VERSION 5.7 ;
  NOWIREEXTENSIONATPIN ON ;
  DIVIDERCHAR "/" ;
  BUSBITCHARS "[]" ;
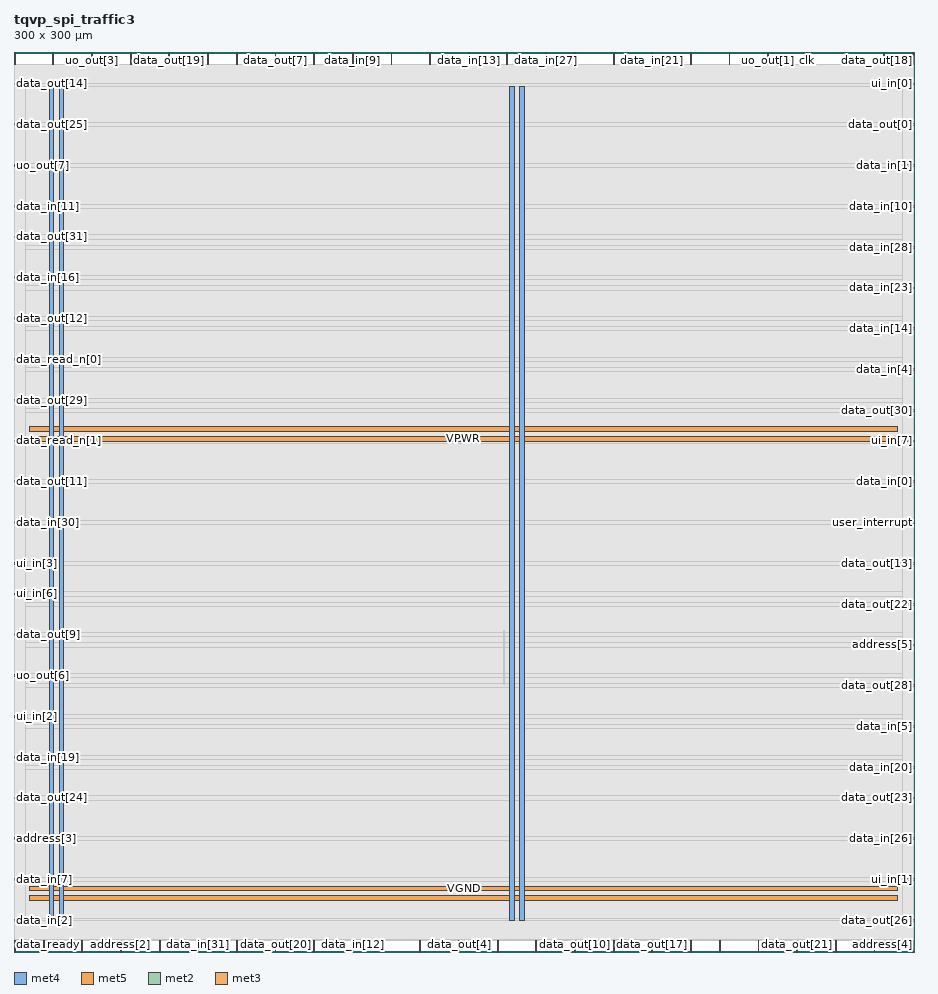
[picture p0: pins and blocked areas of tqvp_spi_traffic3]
MACRO tqvp_spi_traffic3
  CLASS BLOCK ;
  FOREIGN tqvp_spi_traffic3 ;
  ORIGIN 0.000 0.000 ;
  SIZE 300.000 BY 300.000 ;
  PIN VGND
    DIRECTION INOUT ;
    USE GROUND ;
    PORT
      LAYER met4 ;
        RECT 15.020 10.640 16.620 288.560 ;
    END
    PORT
      LAYER met4 ;
        RECT 168.620 10.640 170.220 288.560 ;
    END
    PORT
      LAYER met5 ;
        RECT 5.280 20.380 294.640 21.980 ;
    END
    PORT
      LAYER met5 ;
        RECT 5.280 173.560 294.640 175.160 ;
    END
  END VGND
  PIN VPWR
    DIRECTION INOUT ;
    USE POWER ;
    PORT
      LAYER met4 ;
        RECT 11.720 10.640 13.320 288.560 ;
    END
    PORT
      LAYER met4 ;
        RECT 165.320 10.640 166.920 288.560 ;
    END
    PORT
      LAYER met5 ;
        RECT 5.280 17.080 294.640 18.680 ;
    END
    PORT
      LAYER met5 ;
        RECT 5.280 170.260 294.640 171.860 ;
    END
  END VPWR
  PIN address[0]
    DIRECTION INPUT ;
    USE SIGNAL ;
    PORT
      LAYER met2 ;
        RECT 99.910 296.000 100.190 300.000 ;
    END
  END address[0]
  PIN address[1]
    DIRECTION INPUT ;
    USE SIGNAL ;
    PORT
      LAYER met2 ;
        RECT 199.730 296.000 200.010 300.000 ;
    END
  END address[1]
  PIN address[2]
    DIRECTION INPUT ;
    USE SIGNAL ;
    ANTENNAGATEAREA 0.593700 ;
    ANTENNADIFFAREA 0.434700 ;
    PORT
      LAYER met2 ;
        RECT 35.510 0.000 35.790 4.000 ;
    END
  END address[2]
  PIN address[3]
    DIRECTION INPUT ;
    USE SIGNAL ;
    ANTENNAGATEAREA 0.593700 ;
    ANTENNADIFFAREA 0.434700 ;
    PORT
      LAYER met3 ;
        RECT 0.000 37.440 4.000 38.040 ;
    END
  END address[3]
  PIN address[4]
    DIRECTION INPUT ;
    USE SIGNAL ;
    ANTENNAGATEAREA 0.647700 ;
    ANTENNADIFFAREA 0.434700 ;
    PORT
      LAYER met2 ;
        RECT 299.550 0.000 299.830 4.000 ;
    END
  END address[4]
  PIN address[5]
    DIRECTION INPUT ;
    USE SIGNAL ;
    ANTENNAGATEAREA 0.593700 ;
    ANTENNADIFFAREA 0.434700 ;
    PORT
      LAYER met3 ;
        RECT 296.000 102.040 300.000 102.640 ;
    END
  END address[5]
  PIN clk
    DIRECTION INPUT ;
    USE SIGNAL ;
    ANTENNAGATEAREA 1.286700 ;
    ANTENNADIFFAREA 0.434700 ;
    PORT
      LAYER met2 ;
        RECT 264.130 296.000 264.410 300.000 ;
    END
  END clk
  PIN data_in[0]
    DIRECTION INPUT ;
    USE SIGNAL ;
    ANTENNAGATEAREA 0.593700 ;
    ANTENNADIFFAREA 0.434700 ;
    PORT
      LAYER met3 ;
        RECT 296.000 156.440 300.000 157.040 ;
    END
  END data_in[0]
  PIN data_in[10]
    DIRECTION INPUT ;
    USE SIGNAL ;
    PORT
      LAYER met3 ;
        RECT 296.000 248.240 300.000 248.840 ;
    END
  END data_in[10]
  PIN data_in[11]
    DIRECTION INPUT ;
    USE SIGNAL ;
    PORT
      LAYER met3 ;
        RECT 0.000 248.240 4.000 248.840 ;
    END
  END data_in[11]
  PIN data_in[12]
    DIRECTION INPUT ;
    USE SIGNAL ;
    PORT
      LAYER met2 ;
        RECT 112.790 0.000 113.070 4.000 ;
    END
  END data_in[12]
  PIN data_in[13]
    DIRECTION INPUT ;
    USE SIGNAL ;
    PORT
      LAYER met2 ;
        RECT 151.430 296.000 151.710 300.000 ;
    END
  END data_in[13]
  PIN data_in[14]
    DIRECTION INPUT ;
    USE SIGNAL ;
    PORT
      LAYER met3 ;
        RECT 296.000 207.440 300.000 208.040 ;
    END
  END data_in[14]
  PIN data_in[15]
    DIRECTION INPUT ;
    USE SIGNAL ;
    PORT
      LAYER met2 ;
        RECT 286.670 0.000 286.950 4.000 ;
    END
  END data_in[15]
  PIN data_in[16]
    DIRECTION INPUT ;
    USE SIGNAL ;
    PORT
      LAYER met3 ;
        RECT 0.000 224.440 4.000 225.040 ;
    END
  END data_in[16]
  PIN data_in[17]
    DIRECTION INPUT ;
    USE SIGNAL ;
    PORT
      LAYER met2 ;
        RECT 12.970 296.000 13.250 300.000 ;
    END
  END data_in[17]
  PIN data_in[18]
    DIRECTION INPUT ;
    USE SIGNAL ;
    PORT
      LAYER met2 ;
        RECT 125.670 296.000 125.950 300.000 ;
    END
  END data_in[18]
  PIN data_in[19]
    DIRECTION INPUT ;
    USE SIGNAL ;
    PORT
      LAYER met3 ;
        RECT 0.000 64.640 4.000 65.240 ;
    END
  END data_in[19]
  PIN data_in[1]
    DIRECTION INPUT ;
    USE SIGNAL ;
    ANTENNAGATEAREA 0.647700 ;
    ANTENNADIFFAREA 0.434700 ;
    PORT
      LAYER met3 ;
        RECT 296.000 261.840 300.000 262.440 ;
    END
  END data_in[1]
  PIN data_in[20]
    DIRECTION INPUT ;
    USE SIGNAL ;
    PORT
      LAYER met3 ;
        RECT 296.000 61.240 300.000 61.840 ;
    END
  END data_in[20]
  PIN data_in[21]
    DIRECTION INPUT ;
    USE SIGNAL ;
    PORT
      LAYER met2 ;
        RECT 212.610 296.000 212.890 300.000 ;
    END
  END data_in[21]
  PIN data_in[22]
    DIRECTION INPUT ;
    USE SIGNAL ;
    PORT
      LAYER met2 ;
        RECT 74.150 0.000 74.430 4.000 ;
    END
  END data_in[22]
  PIN data_in[23]
    DIRECTION INPUT ;
    USE SIGNAL ;
    PORT
      LAYER met3 ;
        RECT 296.000 221.040 300.000 221.640 ;
    END
  END data_in[23]
  PIN data_in[24]
    DIRECTION INPUT ;
    USE SIGNAL ;
    PORT
      LAYER met2 ;
        RECT 235.150 0.000 235.430 4.000 ;
    END
  END data_in[24]
  PIN data_in[25]
    DIRECTION INPUT ;
    USE SIGNAL ;
    PORT
      LAYER met2 ;
        RECT 277.010 296.000 277.290 300.000 ;
    END
  END data_in[25]
  PIN data_in[26]
    DIRECTION INPUT ;
    USE SIGNAL ;
    PORT
      LAYER met3 ;
        RECT 296.000 37.440 300.000 38.040 ;
    END
  END data_in[26]
  PIN data_in[27]
    DIRECTION INPUT ;
    USE SIGNAL ;
    PORT
      LAYER met2 ;
        RECT 177.190 296.000 177.470 300.000 ;
    END
  END data_in[27]
  PIN data_in[28]
    DIRECTION INPUT ;
    USE SIGNAL ;
    PORT
      LAYER met3 ;
        RECT 296.000 234.640 300.000 235.240 ;
    END
  END data_in[28]
  PIN data_in[29]
    DIRECTION INPUT ;
    USE SIGNAL ;
    PORT
      LAYER met2 ;
        RECT 0.090 296.000 0.370 300.000 ;
    END
  END data_in[29]
  PIN data_in[2]
    DIRECTION INPUT ;
    USE SIGNAL ;
    ANTENNAGATEAREA 0.593700 ;
    ANTENNADIFFAREA 0.434700 ;
    PORT
      LAYER met3 ;
        RECT 0.000 10.240 4.000 10.840 ;
    END
  END data_in[2]
  PIN data_in[30]
    DIRECTION INPUT ;
    USE SIGNAL ;
    PORT
      LAYER met3 ;
        RECT 0.000 142.840 4.000 143.440 ;
    END
  END data_in[30]
  PIN data_in[31]
    DIRECTION INPUT ;
    USE SIGNAL ;
    PORT
      LAYER met2 ;
        RECT 61.270 0.000 61.550 4.000 ;
    END
  END data_in[31]
  PIN data_in[3]
    DIRECTION INPUT ;
    USE SIGNAL ;
    ANTENNAGATEAREA 0.593700 ;
    ANTENNADIFFAREA 0.434700 ;
    PORT
      LAYER met2 ;
        RECT 138.550 296.000 138.830 300.000 ;
    END
  END data_in[3]
  PIN data_in[4]
    DIRECTION INPUT ;
    USE SIGNAL ;
    PORT
      LAYER met3 ;
        RECT 296.000 193.840 300.000 194.440 ;
    END
  END data_in[4]
  PIN data_in[5]
    DIRECTION INPUT ;
    USE SIGNAL ;
    PORT
      LAYER met3 ;
        RECT 296.000 74.840 300.000 75.440 ;
    END
  END data_in[5]
  PIN data_in[6]
    DIRECTION INPUT ;
    USE SIGNAL ;
    PORT
      LAYER met2 ;
        RECT 186.850 296.000 187.130 300.000 ;
    END
  END data_in[6]
  PIN data_in[7]
    DIRECTION INPUT ;
    USE SIGNAL ;
    PORT
      LAYER met3 ;
        RECT 0.000 23.840 4.000 24.440 ;
    END
  END data_in[7]
  PIN data_in[8]
    DIRECTION INPUT ;
    USE SIGNAL ;
    PORT
      LAYER met2 ;
        RECT 273.790 0.000 274.070 4.000 ;
    END
  END data_in[8]
  PIN data_in[9]
    DIRECTION INPUT ;
    USE SIGNAL ;
    PORT
      LAYER met2 ;
        RECT 112.790 296.000 113.070 300.000 ;
    END
  END data_in[9]
  PIN data_out[0]
    DIRECTION OUTPUT TRISTATE ;
    USE SIGNAL ;
    ANTENNADIFFAREA 0.795200 ;
    PORT
      LAYER met3 ;
        RECT 296.000 275.440 300.000 276.040 ;
    END
  END data_out[0]
  PIN data_out[10]
    DIRECTION OUTPUT TRISTATE ;
    USE SIGNAL ;
    ANTENNADIFFAREA 0.795200 ;
    PORT
      LAYER met2 ;
        RECT 186.850 0.000 187.130 4.000 ;
    END
  END data_out[10]
  PIN data_out[11]
    DIRECTION OUTPUT TRISTATE ;
    USE SIGNAL ;
    ANTENNADIFFAREA 0.795200 ;
    PORT
      LAYER met3 ;
        RECT 0.000 156.440 4.000 157.040 ;
    END
  END data_out[11]
  PIN data_out[12]
    DIRECTION OUTPUT TRISTATE ;
    USE SIGNAL ;
    ANTENNADIFFAREA 0.795200 ;
    PORT
      LAYER met3 ;
        RECT 0.000 210.840 4.000 211.440 ;
    END
  END data_out[12]
  PIN data_out[13]
    DIRECTION OUTPUT TRISTATE ;
    USE SIGNAL ;
    ANTENNADIFFAREA 0.795200 ;
    PORT
      LAYER met3 ;
        RECT 296.000 129.240 300.000 129.840 ;
    END
  END data_out[13]
  PIN data_out[14]
    DIRECTION OUTPUT TRISTATE ;
    USE SIGNAL ;
    ANTENNADIFFAREA 0.795200 ;
    PORT
      LAYER met3 ;
        RECT 0.000 289.040 4.000 289.640 ;
    END
  END data_out[14]
  PIN data_out[15]
    DIRECTION OUTPUT TRISTATE ;
    USE SIGNAL ;
    ANTENNADIFFAREA 0.795200 ;
    PORT
      LAYER met2 ;
        RECT 248.030 0.000 248.310 4.000 ;
    END
  END data_out[15]
  PIN data_out[16]
    DIRECTION OUTPUT TRISTATE ;
    USE SIGNAL ;
    ANTENNADIFFAREA 0.795200 ;
    PORT
      LAYER met2 ;
        RECT 122.450 0.000 122.730 4.000 ;
    END
  END data_out[16]
  PIN data_out[17]
    DIRECTION OUTPUT TRISTATE ;
    USE SIGNAL ;
    ANTENNADIFFAREA 0.795200 ;
    PORT
      LAYER met2 ;
        RECT 212.610 0.000 212.890 4.000 ;
    END
  END data_out[17]
  PIN data_out[18]
    DIRECTION OUTPUT TRISTATE ;
    USE SIGNAL ;
    ANTENNADIFFAREA 0.795200 ;
    PORT
      LAYER met2 ;
        RECT 299.550 296.000 299.830 300.000 ;
    END
  END data_out[18]
  PIN data_out[19]
    DIRECTION OUTPUT TRISTATE ;
    USE SIGNAL ;
    ANTENNADIFFAREA 0.795200 ;
    PORT
      LAYER met2 ;
        RECT 51.610 296.000 51.890 300.000 ;
    END
  END data_out[19]
  PIN data_out[1]
    DIRECTION OUTPUT TRISTATE ;
    USE SIGNAL ;
    ANTENNADIFFAREA 0.795200 ;
    PORT
      LAYER met2 ;
        RECT 22.630 0.000 22.910 4.000 ;
    END
  END data_out[1]
  PIN data_out[20]
    DIRECTION OUTPUT TRISTATE ;
    USE SIGNAL ;
    ANTENNADIFFAREA 0.795200 ;
    PORT
      LAYER met2 ;
        RECT 87.030 0.000 87.310 4.000 ;
    END
  END data_out[20]
  PIN data_out[21]
    DIRECTION OUTPUT TRISTATE ;
    USE SIGNAL ;
    ANTENNADIFFAREA 0.795200 ;
    PORT
      LAYER met2 ;
        RECT 260.910 0.000 261.190 4.000 ;
    END
  END data_out[21]
  PIN data_out[22]
    DIRECTION OUTPUT TRISTATE ;
    USE SIGNAL ;
    ANTENNADIFFAREA 0.795200 ;
    PORT
      LAYER met3 ;
        RECT 296.000 115.640 300.000 116.240 ;
    END
  END data_out[22]
  PIN data_out[23]
    DIRECTION OUTPUT TRISTATE ;
    USE SIGNAL ;
    ANTENNADIFFAREA 0.445500 ;
    PORT
      LAYER met3 ;
        RECT 296.000 51.040 300.000 51.640 ;
    END
  END data_out[23]
  PIN data_out[24]
    DIRECTION OUTPUT TRISTATE ;
    USE SIGNAL ;
    ANTENNADIFFAREA 0.795200 ;
    PORT
      LAYER met3 ;
        RECT 0.000 51.040 4.000 51.640 ;
    END
  END data_out[24]
  PIN data_out[25]
    DIRECTION OUTPUT TRISTATE ;
    USE SIGNAL ;
    PORT
      LAYER met3 ;
        RECT 0.000 275.440 4.000 276.040 ;
    END
  END data_out[25]
  PIN data_out[26]
    DIRECTION OUTPUT TRISTATE ;
    USE SIGNAL ;
    PORT
      LAYER met3 ;
        RECT 296.000 10.240 300.000 10.840 ;
    END
  END data_out[26]
  PIN data_out[27]
    DIRECTION OUTPUT TRISTATE ;
    USE SIGNAL ;
    PORT
      LAYER met2 ;
        RECT 64.490 296.000 64.770 300.000 ;
    END
  END data_out[27]
  PIN data_out[28]
    DIRECTION OUTPUT TRISTATE ;
    USE SIGNAL ;
    PORT
      LAYER met3 ;
        RECT 296.000 88.440 300.000 89.040 ;
    END
  END data_out[28]
  PIN data_out[29]
    DIRECTION OUTPUT TRISTATE ;
    USE SIGNAL ;
    PORT
      LAYER met3 ;
        RECT 0.000 183.640 4.000 184.240 ;
    END
  END data_out[29]
  PIN data_out[2]
    DIRECTION OUTPUT TRISTATE ;
    USE SIGNAL ;
    ANTENNADIFFAREA 0.795200 ;
    PORT
      LAYER met2 ;
        RECT 225.490 0.000 225.770 4.000 ;
    END
  END data_out[2]
  PIN data_out[30]
    DIRECTION OUTPUT TRISTATE ;
    USE SIGNAL ;
    PORT
      LAYER met3 ;
        RECT 296.000 180.240 300.000 180.840 ;
    END
  END data_out[30]
  PIN data_out[31]
    DIRECTION OUTPUT TRISTATE ;
    USE SIGNAL ;
    PORT
      LAYER met3 ;
        RECT 0.000 238.040 4.000 238.640 ;
    END
  END data_out[31]
  PIN data_out[3]
    DIRECTION OUTPUT TRISTATE ;
    USE SIGNAL ;
    ANTENNADIFFAREA 0.795200 ;
    PORT
      LAYER met2 ;
        RECT 38.730 296.000 39.010 300.000 ;
    END
  END data_out[3]
  PIN data_out[4]
    DIRECTION OUTPUT TRISTATE ;
    USE SIGNAL ;
    ANTENNADIFFAREA 0.795200 ;
    PORT
      LAYER met2 ;
        RECT 148.210 0.000 148.490 4.000 ;
    END
  END data_out[4]
  PIN data_out[5]
    DIRECTION OUTPUT TRISTATE ;
    USE SIGNAL ;
    ANTENNADIFFAREA 0.795200 ;
    PORT
      LAYER met2 ;
        RECT 0.090 0.000 0.370 4.000 ;
    END
  END data_out[5]
  PIN data_out[6]
    DIRECTION OUTPUT TRISTATE ;
    USE SIGNAL ;
    ANTENNADIFFAREA 0.795200 ;
    PORT
      LAYER met2 ;
        RECT 173.970 0.000 174.250 4.000 ;
    END
  END data_out[6]
  PIN data_out[7]
    DIRECTION OUTPUT TRISTATE ;
    USE SIGNAL ;
    ANTENNADIFFAREA 0.795200 ;
    PORT
      LAYER met2 ;
        RECT 87.030 296.000 87.310 300.000 ;
    END
  END data_out[7]
  PIN data_out[8]
    DIRECTION OUTPUT TRISTATE ;
    USE SIGNAL ;
    ANTENNADIFFAREA 0.795200 ;
    PORT
      LAYER met2 ;
        RECT 164.310 296.000 164.590 300.000 ;
    END
  END data_out[8]
  PIN data_out[9]
    DIRECTION OUTPUT TRISTATE ;
    USE SIGNAL ;
    ANTENNADIFFAREA 0.795200 ;
    PORT
      LAYER met3 ;
        RECT 0.000 105.440 4.000 106.040 ;
    END
  END data_out[9]
  PIN data_read_n[0]
    DIRECTION INPUT ;
    USE SIGNAL ;
    ANTENNAGATEAREA 0.631200 ;
    ANTENNADIFFAREA 0.434700 ;
    PORT
      LAYER met3 ;
        RECT 0.000 197.240 4.000 197.840 ;
    END
  END data_read_n[0]
  PIN data_read_n[1]
    DIRECTION INPUT ;
    USE SIGNAL ;
    ANTENNAGATEAREA 0.631200 ;
    ANTENNADIFFAREA 0.434700 ;
    PORT
      LAYER met3 ;
        RECT 0.000 170.040 4.000 170.640 ;
    END
  END data_read_n[1]
  PIN data_ready
    DIRECTION INPUT ;
    USE SIGNAL ;
    PORT
      LAYER met2 ;
        RECT 9.750 0.000 10.030 4.000 ;
    END
  END data_ready
  PIN data_write_n[0]
    DIRECTION INPUT ;
    USE SIGNAL ;
    ANTENNAGATEAREA 0.560700 ;
    ANTENNADIFFAREA 0.434700 ;
    PORT
      LAYER met2 ;
        RECT 289.890 296.000 290.170 300.000 ;
    END
  END data_write_n[0]
  PIN data_write_n[1]
    DIRECTION INPUT ;
    USE SIGNAL ;
    ANTENNAGATEAREA 0.631200 ;
    ANTENNADIFFAREA 0.434700 ;
    PORT
      LAYER met2 ;
        RECT 225.490 296.000 225.770 300.000 ;
    END
  END data_write_n[1]
  PIN rst_n
    DIRECTION INPUT ;
    USE SIGNAL ;
    ANTENNAGATEAREA 0.647700 ;
    ANTENNADIFFAREA 0.434700 ;
    PORT
      LAYER met2 ;
        RECT 135.330 0.000 135.610 4.000 ;
    END
  END rst_n
  PIN ui_in[0]
    DIRECTION INPUT ;
    USE SIGNAL ;
    ANTENNAGATEAREA 0.647700 ;
    ANTENNADIFFAREA 0.434700 ;
    PORT
      LAYER met3 ;
        RECT 296.000 289.040 300.000 289.640 ;
    END
  END ui_in[0]
  PIN ui_in[1]
    DIRECTION INPUT ;
    USE SIGNAL ;
    ANTENNAGATEAREA 0.560700 ;
    ANTENNADIFFAREA 0.434700 ;
    PORT
      LAYER met3 ;
        RECT 296.000 23.840 300.000 24.440 ;
    END
  END ui_in[1]
  PIN ui_in[2]
    DIRECTION INPUT ;
    USE SIGNAL ;
    ANTENNAGATEAREA 0.631200 ;
    ANTENNADIFFAREA 0.434700 ;
    PORT
      LAYER met3 ;
        RECT 0.000 78.240 4.000 78.840 ;
    END
  END ui_in[2]
  PIN ui_in[3]
    DIRECTION INPUT ;
    USE SIGNAL ;
    ANTENNAGATEAREA 0.631200 ;
    ANTENNADIFFAREA 0.434700 ;
    PORT
      LAYER met3 ;
        RECT 0.000 129.240 4.000 129.840 ;
    END
  END ui_in[3]
  PIN ui_in[4]
    DIRECTION INPUT ;
    USE SIGNAL ;
    PORT
      LAYER met2 ;
        RECT 48.390 0.000 48.670 4.000 ;
    END
  END ui_in[4]
  PIN ui_in[5]
    DIRECTION INPUT ;
    USE SIGNAL ;
    PORT
      LAYER met2 ;
        RECT 99.910 0.000 100.190 4.000 ;
    END
  END ui_in[5]
  PIN ui_in[6]
    DIRECTION INPUT ;
    USE SIGNAL ;
    PORT
      LAYER met3 ;
        RECT 0.000 119.040 4.000 119.640 ;
    END
  END ui_in[6]
  PIN ui_in[7]
    DIRECTION INPUT ;
    USE SIGNAL ;
    PORT
      LAYER met3 ;
        RECT 296.000 170.040 300.000 170.640 ;
    END
  END ui_in[7]
  PIN uo_out[0]
    DIRECTION OUTPUT TRISTATE ;
    USE SIGNAL ;
    ANTENNADIFFAREA 0.795200 ;
    PORT
      LAYER met2 ;
        RECT 161.090 0.000 161.370 4.000 ;
    END
  END uo_out[0]
  PIN uo_out[1]
    DIRECTION OUTPUT TRISTATE ;
    USE SIGNAL ;
    ANTENNADIFFAREA 0.795200 ;
    PORT
      LAYER met2 ;
        RECT 251.250 296.000 251.530 300.000 ;
    END
  END uo_out[1]
  PIN uo_out[2]
    DIRECTION OUTPUT TRISTATE ;
    USE SIGNAL ;
    ANTENNADIFFAREA 0.795200 ;
    PORT
      LAYER met2 ;
        RECT 238.370 296.000 238.650 300.000 ;
    END
  END uo_out[2]
  PIN uo_out[3]
    DIRECTION OUTPUT TRISTATE ;
    USE SIGNAL ;
    ANTENNADIFFAREA 0.795200 ;
    PORT
      LAYER met2 ;
        RECT 25.850 296.000 26.130 300.000 ;
    END
  END uo_out[3]
  PIN uo_out[4]
    DIRECTION OUTPUT TRISTATE ;
    USE SIGNAL ;
    PORT
      LAYER met2 ;
        RECT 74.150 296.000 74.430 300.000 ;
    END
  END uo_out[4]
  PIN uo_out[5]
    DIRECTION OUTPUT TRISTATE ;
    USE SIGNAL ;
    PORT
      LAYER met2 ;
        RECT 199.730 0.000 200.010 4.000 ;
    END
  END uo_out[5]
  PIN uo_out[6]
    DIRECTION OUTPUT TRISTATE ;
    USE SIGNAL ;
    PORT
      LAYER met3 ;
        RECT 0.000 91.840 4.000 92.440 ;
    END
  END uo_out[6]
  PIN uo_out[7]
    DIRECTION OUTPUT TRISTATE ;
    USE SIGNAL ;
    PORT
      LAYER met3 ;
        RECT 0.000 261.840 4.000 262.440 ;
    END
  END uo_out[7]
  PIN user_interrupt
    DIRECTION OUTPUT TRISTATE ;
    USE SIGNAL ;
    ANTENNADIFFAREA 0.795200 ;
    PORT
      LAYER met3 ;
        RECT 296.000 142.840 300.000 143.440 ;
    END
  END user_interrupt
  OBS
      LAYER li1 ;
        RECT 5.520 10.795 294.400 288.405 ;
      LAYER met1 ;
        RECT 0.070 10.640 299.850 288.560 ;
      LAYER met2 ;
        RECT 0.650 295.720 12.690 296.000 ;
        RECT 13.530 295.720 25.570 296.000 ;
        RECT 26.410 295.720 38.450 296.000 ;
        RECT 39.290 295.720 51.330 296.000 ;
        RECT 52.170 295.720 64.210 296.000 ;
        RECT 65.050 295.720 73.870 296.000 ;
        RECT 74.710 295.720 86.750 296.000 ;
        RECT 87.590 295.720 99.630 296.000 ;
        RECT 100.470 295.720 112.510 296.000 ;
        RECT 113.350 295.720 125.390 296.000 ;
        RECT 126.230 295.720 138.270 296.000 ;
        RECT 139.110 295.720 151.150 296.000 ;
        RECT 151.990 295.720 164.030 296.000 ;
        RECT 164.870 295.720 176.910 296.000 ;
        RECT 177.750 295.720 186.570 296.000 ;
        RECT 187.410 295.720 199.450 296.000 ;
        RECT 200.290 295.720 212.330 296.000 ;
        RECT 213.170 295.720 225.210 296.000 ;
        RECT 226.050 295.720 238.090 296.000 ;
        RECT 238.930 295.720 250.970 296.000 ;
        RECT 251.810 295.720 263.850 296.000 ;
        RECT 264.690 295.720 276.730 296.000 ;
        RECT 277.570 295.720 289.610 296.000 ;
        RECT 290.450 295.720 299.270 296.000 ;
        RECT 0.100 4.280 299.820 295.720 ;
        RECT 0.650 3.670 9.470 4.280 ;
        RECT 10.310 3.670 22.350 4.280 ;
        RECT 23.190 3.670 35.230 4.280 ;
        RECT 36.070 3.670 48.110 4.280 ;
        RECT 48.950 3.670 60.990 4.280 ;
        RECT 61.830 3.670 73.870 4.280 ;
        RECT 74.710 3.670 86.750 4.280 ;
        RECT 87.590 3.670 99.630 4.280 ;
        RECT 100.470 3.670 112.510 4.280 ;
        RECT 113.350 3.670 122.170 4.280 ;
        RECT 123.010 3.670 135.050 4.280 ;
        RECT 135.890 3.670 147.930 4.280 ;
        RECT 148.770 3.670 160.810 4.280 ;
        RECT 161.650 3.670 173.690 4.280 ;
        RECT 174.530 3.670 186.570 4.280 ;
        RECT 187.410 3.670 199.450 4.280 ;
        RECT 200.290 3.670 212.330 4.280 ;
        RECT 213.170 3.670 225.210 4.280 ;
        RECT 226.050 3.670 234.870 4.280 ;
        RECT 235.710 3.670 247.750 4.280 ;
        RECT 248.590 3.670 260.630 4.280 ;
        RECT 261.470 3.670 273.510 4.280 ;
        RECT 274.350 3.670 286.390 4.280 ;
        RECT 287.230 3.670 299.270 4.280 ;
      LAYER met3 ;
        RECT 4.400 288.640 295.600 289.505 ;
        RECT 3.990 276.440 296.000 288.640 ;
        RECT 4.400 275.040 295.600 276.440 ;
        RECT 3.990 262.840 296.000 275.040 ;
        RECT 4.400 261.440 295.600 262.840 ;
        RECT 3.990 249.240 296.000 261.440 ;
        RECT 4.400 247.840 295.600 249.240 ;
        RECT 3.990 239.040 296.000 247.840 ;
        RECT 4.400 237.640 296.000 239.040 ;
        RECT 3.990 235.640 296.000 237.640 ;
        RECT 3.990 234.240 295.600 235.640 ;
        RECT 3.990 225.440 296.000 234.240 ;
        RECT 4.400 224.040 296.000 225.440 ;
        RECT 3.990 222.040 296.000 224.040 ;
        RECT 3.990 220.640 295.600 222.040 ;
        RECT 3.990 211.840 296.000 220.640 ;
        RECT 4.400 210.440 296.000 211.840 ;
        RECT 3.990 208.440 296.000 210.440 ;
        RECT 3.990 207.040 295.600 208.440 ;
        RECT 3.990 198.240 296.000 207.040 ;
        RECT 4.400 196.840 296.000 198.240 ;
        RECT 3.990 194.840 296.000 196.840 ;
        RECT 3.990 193.440 295.600 194.840 ;
        RECT 3.990 184.640 296.000 193.440 ;
        RECT 4.400 183.240 296.000 184.640 ;
        RECT 3.990 181.240 296.000 183.240 ;
        RECT 3.990 179.840 295.600 181.240 ;
        RECT 3.990 171.040 296.000 179.840 ;
        RECT 4.400 169.640 295.600 171.040 ;
        RECT 3.990 157.440 296.000 169.640 ;
        RECT 4.400 156.040 295.600 157.440 ;
        RECT 3.990 143.840 296.000 156.040 ;
        RECT 4.400 142.440 295.600 143.840 ;
        RECT 3.990 130.240 296.000 142.440 ;
        RECT 4.400 128.840 295.600 130.240 ;
        RECT 3.990 120.040 296.000 128.840 ;
        RECT 4.400 118.640 296.000 120.040 ;
        RECT 3.990 116.640 296.000 118.640 ;
        RECT 3.990 115.240 295.600 116.640 ;
        RECT 3.990 106.440 296.000 115.240 ;
        RECT 4.400 105.040 296.000 106.440 ;
        RECT 3.990 103.040 296.000 105.040 ;
        RECT 3.990 101.640 295.600 103.040 ;
        RECT 3.990 92.840 296.000 101.640 ;
        RECT 4.400 91.440 296.000 92.840 ;
        RECT 3.990 89.440 296.000 91.440 ;
        RECT 3.990 88.040 295.600 89.440 ;
        RECT 3.990 79.240 296.000 88.040 ;
        RECT 4.400 77.840 296.000 79.240 ;
        RECT 3.990 75.840 296.000 77.840 ;
        RECT 3.990 74.440 295.600 75.840 ;
        RECT 3.990 65.640 296.000 74.440 ;
        RECT 4.400 64.240 296.000 65.640 ;
        RECT 3.990 62.240 296.000 64.240 ;
        RECT 3.990 60.840 295.600 62.240 ;
        RECT 3.990 52.040 296.000 60.840 ;
        RECT 4.400 50.640 295.600 52.040 ;
        RECT 3.990 38.440 296.000 50.640 ;
        RECT 4.400 37.040 295.600 38.440 ;
        RECT 3.990 24.840 296.000 37.040 ;
        RECT 4.400 23.440 295.600 24.840 ;
        RECT 3.990 11.240 296.000 23.440 ;
        RECT 4.400 10.375 295.600 11.240 ;
      LAYER met4 ;
        RECT 163.135 89.255 163.465 107.265 ;
  END
END tqvp_spi_traffic3
END LIBRARY

